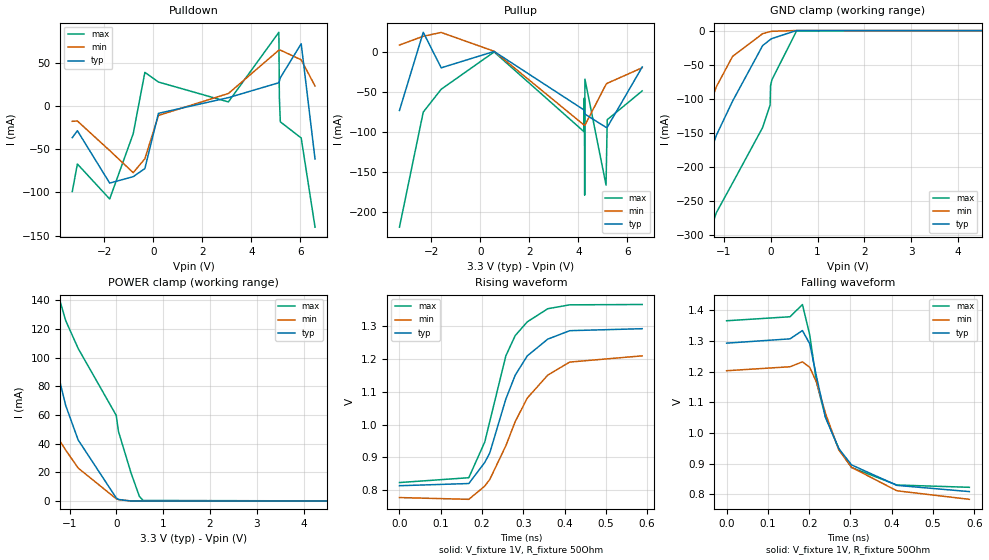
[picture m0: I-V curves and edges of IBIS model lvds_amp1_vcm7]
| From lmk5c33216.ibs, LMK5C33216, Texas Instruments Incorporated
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[Model]   lvds_amp1_vcm7
Model_type   Output
Polarity   Non-Inverting
Vmeas = 1.05
Vref = 1
Cref = 0pF
Rref = 50
|   typ   min   max
C_comp   0.65pF   0.575pF   0.725pF
[Voltage Range]   3.3   3.135   3.465
[Temperature Range]   50   135   -40
[Pullup Reference]   3.3   3.135   3.465
[Pulldown Reference]   0   0   0
[Power Clamp Reference]   3.3   3.135   3.465
[GND Clamp Reference]   0   0   0
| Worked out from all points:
|   slope of the pulldown table from 0 to 0.495 V, typ, clamps not added: 39 ohm
|   slope of the pullup table from 0 to 0.495 V, typ, clamps not added: 45.2 ohm
|   falling waveform, V_fixture 1V, R_fixture 50Ohm: 20-80 % time 80ps typ, 90.8ps min, 72ps max; typ from 1.29 V to 0.809 V
|   rising waveform, V_fixture 1V, R_fixture 50Ohm: 20-80 % time 84.3ps typ, 103ps min, 72.7ps max; typ from 0.813 V to 1.29 V
[Pulldown]
|   Voltage   I(typ)   I(min)   I(max)
-3.3V     -36.28mA   -17.29mA   -98.91mA
-3.092V   -28.2mA    -16.94mA   -66.89mA
-1.775V   -89.1mA    -51.28mA   -107.6mA
-815.1mV  -81.61mA   -77mA      -31.67mA
-339.9mV  -72.2mA    -60.81mA   39.58mA
214.5mV   -8.027mA   -10.45mA   28.36mA
3.066V    10.19mA    15.04mA    5.226mA
5.125V    27.53mA    65.4mA     86.12mA
5.145V    29.31mA    65.43mA    11.13mA
5.184V    33.29mA    65.5mA     -17.89mA
6.036V    72.89mA    54.18mA    -36.69mA
6.6V      -61.2mA    23.69mA    -140.3mA
[GND Clamp]
|   Voltage   I(typ)   I(min)   I(max)
-3.3V     -892.9mA   -765.6mA   -1.068A
-1.924V   -314.6mA   -288.5mA   -459.9mA
-1.815V   -287mA     -251.4mA   -425.6mA
-1.478V   -218.2mA   -143.5mA   -333.1mA
-1.162V   -154.3mA   -82.94mA   -268mA
-815.1mV  -104mA     -38.12mA   -224.4mA
-171.6mV  -22.09mA   -4.573mA   -142.5mA
-13.2mV   -13.46mA   -1.685mA   -109.6mA
-3.3mV    -13.01mA   -1.546mA   -81.34mA
26.4mV    -11.77mA   -1.169mA   -72.3mA
551.1mV   0A         -83.65nA   -742.8uA
6.6V      0A         0A         0A
[Pullup]
|   Voltage   I(typ)   I(min)   I(max)
-3.3V     -73.54mA   8.067mA    -219.2mA
-2.33V    23.94mA    19.04mA    -75.63mA
-1.597V   -20.36mA   23.77mA    -47.07mA
561mV     65.53uA    296.6uA    -559.4uA
4.224V    -72.89mA   -91.67mA   -99.99mA
4.234V    -74.22mA   -91.78mA   -58.17mA
4.244V    -75.55mA   -91.87mA   -59.21mA
4.254V    -76.87mA   -91.95mA   -179.3mA
4.264V    -78.2mA    -92.03mA   -34.54mA
5.125V    -94.66mA   -41.01mA   -166.7mA
5.174V    -94.58mA   -39.64mA   -85.12mA
6.6V      -19.36mA   -20.28mA   -49.19mA
[POWER Clamp]
|   Voltage   I(typ)   I(min)   I(max)
-3.3V     330.7mA    180mA      566.4mA
-2.736V   200mA      135.8mA    401.6mA
-1.647V   138.3mA    65.17mA    197.7mA
-1.459V   117.6mA    55.06mA    168.7mA
-1.082V   66.76mA    35.64mA    126mA
-815.1mV  42.67mA    23.06mA    106.5mA
-3.3mV    2.23mA     1.644mA    59.86mA
46.2mV    1.16mA     1.045mA    48.46mA
313.5mV   86.42uA    94.45uA    19.62mA
491.7mV   74.41uA    72.76uA    3.272mA
570.9mV   69.96uA    68.47uA    464.6uA
6.6V      0A         0A         0A
[Ramp]
R_load = 50
|   typ   min   max
dV/dt_r   0.288342/8.39842e-11   0.259797/1.02328e-10   0.326583/7.24332e-11
dV/dt_f   0.290201/7.94865e-11   0.251526/9.06222e-11   0.325865/7.1979e-11
[Falling Waveform]
V_fixture = 1V
V_fixture_min = 0.95V
V_fixture_max = 1.05V
R_fixture = 50Ohm
C_fixture = 0F
|   Time   V(typ)   V(min)   V(max)
0s        1.293V     1.203V     1.366V
153.7ps   1.307V     1.216V     1.379V
183.6ps   1.334V     1.232V     1.419V
201.3ps   1.291V     1.214V     1.32V
218ps     1.182V     1.165V     1.164V
239.4ps   1.051V     1.064V     1.052V
271.6ps   948.9mV    945mV      949.6mV
302.7ps   895.8mV    887.8mV    887.4mV
412.5ps   829.1mV    811.4mV    830.3mV
588ps     808.8mV    783.6mV    822.8mV
[Rising Waveform]
V_fixture = 1V
V_fixture_min = 0.95V
V_fixture_max = 1.05V
R_fixture = 50Ohm
C_fixture = 0F
|   Time   V(typ)   V(min)   V(max)
0s        812.9mV    776.7mV    822.6mV
168ps     819.6mV    771.3mV    837.4mV
206.7ps   884.2mV    811.9mV    946.9mV
218.7ps   913mV      831.9mV    1.009V
257.7ps   1.078V     935.1mV    1.21V
280.4ps   1.151V     1.009V     1.272V
309.7ps   1.21V      1.081V     1.314V
359.1ps   1.261V     1.151V     1.354V
412.5ps   1.287V     1.191V     1.366V
588ps     1.293V     1.21V      1.367V
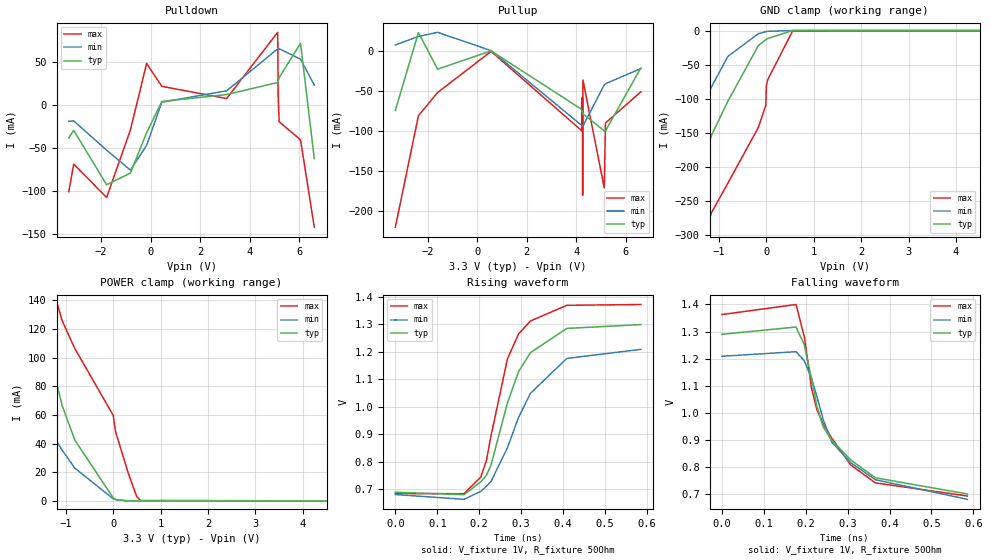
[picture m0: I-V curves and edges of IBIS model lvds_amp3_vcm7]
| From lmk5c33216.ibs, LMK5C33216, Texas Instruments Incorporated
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[Model]   lvds_amp3_vcm7
Model_type   Output
Polarity   Non-Inverting
Vmeas = 1
Vref = 1
Cref = 0pF
Rref = 50
|   typ   min   max
C_comp   0.65pF   0.575pF   0.725pF
[Voltage Range]   3.3   3.135   3.465
[Temperature Range]   50   135   -40
[Pullup Reference]   3.3   3.135   3.465
[Pulldown Reference]   -0   0   0
[Power Clamp Reference]   3.3   3.135   3.465
[GND Clamp Reference]   0   0   0
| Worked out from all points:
|   slope of the pulldown table from 0 to 0.495 V, typ, clamps not added: 36.3 ohm
|   slope of the pullup table from 0 to 0.495 V, typ, clamps not added: 44.7 ohm
|   falling waveform, V_fixture 1V, R_fixture 50Ohm: 20-80 % time 105ps typ, 114ps min, 96.3ps max; typ from 1.29 V to 0.701 V
|   rising waveform, V_fixture 1V, R_fixture 50Ohm: 20-80 % time 79.3ps typ, 97.9ps min, 63.7ps max; typ from 0.69 V to 1.3 V
[Pulldown]
|   Voltage   I(typ)   I(min)   I(max)
-3.3V     -38.24mA   -18.97mA   -101mA
-3.102V   -29.52mA   -18.51mA   -68.88mA
-1.775V   -92.97mA   -52.57mA   -107.8mA
-815.1mV  -79.32mA   -75.88mA   -29.05mA
-161.7mV  -32.41mA   -46.99mA   48.34mA
452.1mV   4.115mA    3.224mA    21.7mA
3.066V    12.13mA    16.52mA    7.51mA
5.125V    26.21mA    65.37mA    84.62mA
5.145V    27.96mA    65.4mA     9.43mA
5.184V    31.9mA     65.46mA    -19.52mA
6.046V    71.81mA    53.32mA    -40.66mA
6.6V      -62.49mA   23.18mA    -142.3mA
[GND Clamp]
|   Voltage   I(typ)   I(min)   I(max)
-3.3V     -892.9mA   -765.6mA   -1.068A
-1.924V   -314.6mA   -288.5mA   -459.9mA
-1.815V   -287mA     -251.4mA   -425.6mA
-1.478V   -218.2mA   -143.5mA   -333.1mA
-1.162V   -154.3mA   -82.94mA   -268mA
-815.1mV  -104mA     -38.12mA   -224.4mA
-171.6mV  -22.09mA   -4.573mA   -142.5mA
-13.2mV   -13.46mA   -1.685mA   -109.6mA
-3.3mV    -13.01mA   -1.546mA   -81.32mA
26.4mV    -11.77mA   -1.169mA   -72.35mA
551.1mV   0A         -83.65nA   -742.8uA
6.6V      0A         0A         0A
[Pullup]
|   Voltage   I(typ)   I(min)   I(max)
-3.3V     -74.36mA   7.532mA    -220.4mA
-2.369V   23.05mA    18.16mA    -81mA
-1.597V   -22.71mA   23.36mA    -51.97mA
561mV     135.2uA    475.5uA    -547.1uA
4.224V    -73.22mA   -93.37mA   -99.9mA
4.234V    -74.59mA   -93.52mA   -58.1mA
4.244V    -75.96mA   -93.67mA   -59.14mA
4.254V    -77.33mA   -93.8mA    -180.7mA
4.264V    -78.7mA    -93.93mA   -36.28mA
5.125V    -99.86mA   -42.33mA   -171.2mA
5.174V    -99.93mA   -40.98mA   -90.01mA
6.6V      -21.2mA    -21.98mA   -51.16mA
[POWER Clamp]
|   Voltage   I(typ)   I(min)   I(max)
-3.3V     330.7mA    180mA      566.4mA
-2.736V   200mA      135.8mA    401.6mA
-1.647V   138.3mA    65.17mA    197.7mA
-1.459V   117.6mA    55.06mA    168.7mA
-1.082V   66.76mA    35.64mA    126mA
-815.1mV  42.67mA    23.06mA    106.5mA
-3.3mV    2.23mA     1.644mA    59.85mA
46.2mV    1.16mA     1.045mA    48.48mA
313.5mV   86.42uA    94.45uA    19.62mA
491.7mV   74.41uA    72.76uA    3.272mA
570.9mV   69.96uA    68.47uA    464.6uA
6.6V      0A         0A         0A
[Ramp]
R_load = 50
|   typ   min   max
dV/dt_r   0.365402/7.91052e-11   0.316822/9.78563e-11   0.412328/6.33514e-11
dV/dt_f   0.353145/1.04143e-10   0.316822/1.12557e-10   0.401376/9.55052e-11
[Falling Waveform]
V_fixture = 1V
V_fixture_min = 0.95V
V_fixture_max = 1.05V
R_fixture = 50Ohm
C_fixture = 0F
|   Time   V(typ)   V(min)   V(max)
0s        1.29V      1.209V     1.363V
176.9ps   1.317V     1.226V     1.4V
196.7ps   1.251V     1.192V     1.281V
213.9ps   1.126V     1.128V     1.091V
226.7ps   1.025V     1.061V     1.012V
241.5ps   949.1mV    976.7mV    961.3mV
261.4ps   900.6mV    894mV      909.1mV
307.6ps   826mV      816.2mV    807.7mV
366.6ps   760.7mV    753.5mV    742mV
585.8ps   701.1mV    681.4mV    693.7mV
[Rising Waveform]
V_fixture = 1V
V_fixture_min = 0.95V
V_fixture_max = 1.05V
R_fixture = 50Ohm
C_fixture = 0F
|   Time   V(typ)   V(min)   V(max)
0s        689.7mV    681.4mV    684.9mV
163.7ps   680.9mV    664mV      684.6mV
203.8ps   727.5mV    692.7mV    744.5mV
217.3ps   751.4mV    711.3mV    805.1mV
228ps     787.4mV    727.8mV    892.9mV
267.4ps   1.014V     851.3mV    1.174V
294ps     1.128V     961.8mV    1.265V
322.3ps   1.197V     1.049V     1.312V
409.1ps   1.285V     1.176V     1.369V
585.8ps   1.299V     1.209V     1.372V
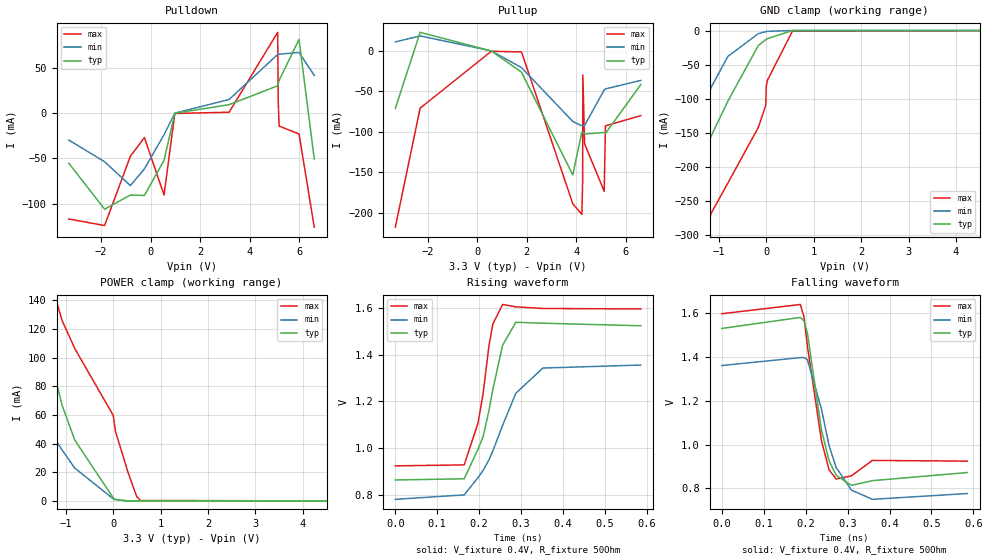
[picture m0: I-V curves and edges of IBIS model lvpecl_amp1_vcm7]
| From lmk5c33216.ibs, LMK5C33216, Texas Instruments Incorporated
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[Model]   lvpecl_amp1_vcm7
Model_type   Output
Polarity   Non-Inverting
Vmeas = 1.2
Vref = 0.4
Cref = 0pF
Rref = 50
|   typ   min   max
C_comp   0.65pF   0.575pF   0.725pF
[Voltage Range]   3.3   3.135   3.465
[Temperature Range]   50   135   -40
[Pullup Reference]   3.3   3.135   3.465
[Pulldown Reference]   0   0   0
[Power Clamp Reference]   3.3   3.135   3.465
[GND Clamp Reference]   0   0   0
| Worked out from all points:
|   slope of the pulldown table from 0 to 0.495 V, typ, clamps not added: 17.6 ohm
|   slope of the pullup table from 0 to 0.495 V, typ, clamps not added: 52.3 ohm
|   falling waveform, V_fixture 0.4V, R_fixture 50Ohm: 20-80 % time 31.6ps typ, 43.8ps min, 30.3ps max; typ from 1.53 V to 0.873 V
|   rising waveform, V_fixture 0.4V, R_fixture 50Ohm: 20-80 % time 51.5ps typ, 83.6ps min, 38.7ps max; typ from 0.864 V to 1.52 V
[Pulldown]
|   Voltage   I(typ)   I(min)   I(max)
-3.3V     -55.54mA   -29.94mA   -117.1mA
-1.855V   -106.3mA   -53.89mA   -124.3mA
-815.1mV  -90.62mA   -80.2mA    -47.75mA
-250.8mV  -91.11mA   -61.75mA   -27.15mA
541.2mV   -52.28mA   -24.04mA   -90.66mA
976.8mV   -331.6uA   -179.7uA   -555.2uA
3.165V    9.147mA    14.84mA    773.9uA
5.125V    29.99mA    64.61mA    89.03mA
5.145V    31.87mA    64.67mA    14.18mA
5.184V    36.04mA    64.81mA    -14.5mA
5.986V    81.17mA    66.88mA    -23.15mA
6.6V      -50.8mA    41.43mA    -126.1mA
[GND Clamp]
|   Voltage   I(typ)   I(min)   I(max)
-3.3V     -892.9mA   -765.6mA   -1.068A
-1.924V   -314.6mA   -288.5mA   -459.9mA
-1.815V   -287mA     -251.4mA   -425.6mA
-1.478V   -218.2mA   -143.5mA   -333.1mA
-1.162V   -154.3mA   -82.94mA   -268mA
-815.1mV  -104mA     -38.12mA   -224.4mA
-171.6mV  -22.09mA   -4.573mA   -142.5mA
-13.2mV   -13.46mA   -1.685mA   -109.6mA
-3.3mV    -13.01mA   -1.546mA   -81.32mA
26.4mV    -11.77mA   -1.169mA   -72.35mA
551.1mV   0A         -83.65nA   -742.3uA
6.6V      0A         0A         0A
[Pullup]
|   Voltage   I(typ)   I(min)   I(max)
-3.3V     -71.11mA   11.11mA    -217.9mA
-2.3V     23.01mA    18.59mA    -70.78mA
570.9mV   -34.73uA   26.91uA    -439.3uA
1.789V    -26.25mA   -20.59mA   -1.263mA
3.858V    -153.3mA   -87.25mA   -189mA
4.224V    -100.2mA   -92.59mA   -202.1mA
4.254V    -100.4mA   -92.51mA   -162.3mA
4.264V    -100.6mA   -92.48mA   -29.78mA
4.333V    -102.7mA   -92.17mA   -114.8mA
5.125V    -100.8mA   -48.19mA   -173.6mA
5.174V    -102.1mA   -46.97mA   -92.64mA
6.6V      -41.61mA   -36.46mA   -79.99mA
[POWER Clamp]
|   Voltage   I(typ)   I(min)   I(max)
-3.3V     330.7mA    180mA      566.4mA
-2.736V   200mA      135.8mA    401.6mA
-1.647V   138.3mA    65.17mA    197.7mA
-1.459V   117.6mA    55.06mA    168.7mA
-1.082V   66.76mA    35.64mA    126mA
-815.1mV  42.67mA    23.06mA    106.5mA
-3.3mV    2.23mA     1.644mA    59.85mA
46.2mV    1.16mA     1.045mA    48.48mA
313.5mV   86.42uA    94.45uA    19.62mA
491.7mV   74.41uA    72.76uA    3.272mA
570.9mV   69.96uA    68.47uA    464.4uA
6.6V      0A         0A         0A
[Ramp]
R_load = 50
|   typ   min   max
dV/dt_r   0.395728/5.12019e-11   0.345023/8.32962e-11   0.402849/3.86156e-11
dV/dt_f   0.393848/3.15675e-11   0.349741/4.38037e-11   0.402849/3.0072e-11
[Falling Waveform]
V_fixture = 0.4V
V_fixture_min = 0.35V
V_fixture_max = 0.45V
R_fixture = 50Ohm
C_fixture = 0F
|   Time   V(typ)   V(min)   V(max)
0s        1.529V     1.36V      1.596V
187.2ps   1.579V     1.396V     1.638V
195.9ps   1.563V     1.396V     1.582V
204.1ps   1.507V     1.387V     1.448V
237.7ps   1.066V     1.161V     1.017V
255.8ps   926.2mV    995.3mV    884.9mV
272.6ps   860.1mV    895.7mV    843.1mV
309.1ps   814.2mV    792.7mV    857.3mV
359.1ps   835.5mV    750.5mV    927.8mV
585.6ps   872.6mV    776.9mV    924.5mV
[Rising Waveform]
V_fixture = 0.4V
V_fixture_min = 0.35V
V_fixture_max = 0.45V
R_fixture = 50Ohm
C_fixture = 0F
|   Time   V(typ)   V(min)   V(max)
0s        864.1mV    781.2mV    924.5mV
164.3ps   869.1mV    800.2mV    928.6mV
197.4ps   996.6mV    874.3mV    1.108V
209.7ps   1.051V     905.7mV    1.237V
223ps     1.158V     948.8mV    1.434V
232.7ps   1.252V     988.7mV    1.532V
255.8ps   1.44V      1.097V     1.615V
287.5ps   1.539V     1.235V     1.605V
351.8ps   1.535V     1.343V     1.598V
585.6ps   1.524V     1.356V     1.596V
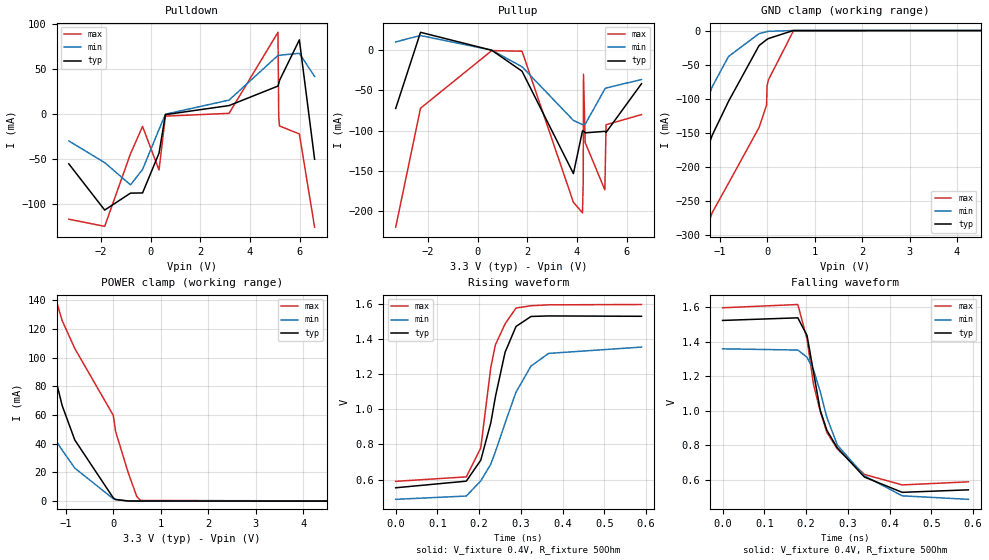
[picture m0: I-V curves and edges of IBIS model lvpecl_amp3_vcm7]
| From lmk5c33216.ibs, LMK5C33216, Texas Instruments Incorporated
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[Model]   lvpecl_amp3_vcm7
Model_type   Output
Polarity   Non-Inverting
Vmeas = 1.05
Vref = 0.4
Cref = 0pF
Rref = 50
|   typ   min   max
C_comp   0.65pF   0.575pF   0.725pF
[Voltage Range]   3.3   3.135   3.465
[Temperature Range]   50   135   -40
[Pullup Reference]   3.3   3.135   3.465
[Pulldown Reference]   0   0   -0
[Power Clamp Reference]   3.3   3.135   3.465
[GND Clamp Reference]   0   0   0
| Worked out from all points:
|   slope of the pulldown table from 0 to 0.495 V, typ, clamps not added: 8.61 ohm
|   slope of the pullup table from 0 to 0.495 V, typ, clamps not added: 51.2 ohm
|   falling waveform, V_fixture 0.4V, R_fixture 50Ohm: 20-80 % time 78.5ps typ, 97ps min, 67ps max; typ from 1.52 V to 0.544 V
|   rising waveform, V_fixture 0.4V, R_fixture 50Ohm: 20-80 % time 52.4ps typ, 82.5ps min, 38.5ps max; typ from 0.553 V to 1.53 V
[Pulldown]
|   Voltage   I(typ)   I(min)   I(max)
-3.3V     -55.26mA   -29.89mA   -116.5mA
-1.855V   -106.4mA   -53.89mA   -124.4mA
-815.1mV  -87.64mA   -78.47mA   -44.04mA
-330mV    -87.45mA   -61.5mA    -13.86mA
333.3mV   -43.46mA   -17.19mA   -62.07mA
590.7mV   -792.1uA   -335.3uA   -2.433mA
3.155V    9.24mA     15.3mA     640.1uA
5.125V    30.83mA    64.73mA    90.29mA
5.155V    33.7mA     64.83mA    -2.221mA
5.184V    36.87mA    64.93mA    -13.27mA
5.986V    81.94mA    67.08mA    -22.17mA
6.6V      -50.08mA   41.43mA    -125.3mA
[GND Clamp]
|   Voltage   I(typ)   I(min)   I(max)
-3.3V     -892.9mA   -765.6mA   -1.068A
-1.924V   -314.6mA   -288.5mA   -459.9mA
-1.815V   -287mA     -251.4mA   -425.6mA
-1.478V   -218.2mA   -143.5mA   -333.1mA
-1.162V   -154.3mA   -82.94mA   -268mA
-815.1mV  -104mA     -38.12mA   -224.4mA
-171.6mV  -22.09mA   -4.573mA   -142.5mA
-13.2mV   -13.46mA   -1.685mA   -109.6mA
-3.3mV    -13.01mA   -1.546mA   -81.32mA
26.4mV    -11.77mA   -1.169mA   -72.35mA
551.1mV   0A         -83.65nA   -740.5uA
6.6V      0A         0A         0A
[Pullup]
|   Voltage   I(typ)   I(min)   I(max)
-3.3V     -72.34mA   10.4mA     -219.9mA
-2.3V     22.26mA    18.26mA    -72.06mA
570.9mV   -25.45uA   42.59uA    -437.4uA
1.789V    -26.09mA   -20.56mA   -1.222mA
3.858V    -153.3mA   -87.2mA    -189mA
4.224V    -100.2mA   -92.4mA    -202.1mA
4.254V    -100.4mA   -92.29mA   -162.3mA
4.264V    -100.6mA   -92.25mA   -29.8mA
4.333V    -102.7mA   -91.88mA   -114.8mA
5.125V    -100.8mA   -48.13mA   -173.6mA
5.174V    -102.1mA   -46.91mA   -92.62mA
6.6V      -41.65mA   -36.46mA   -80.03mA
[POWER Clamp]
|   Voltage   I(typ)   I(min)   I(max)
-3.3V     330.7mA    180mA      566.4mA
-2.736V   200mA      135.8mA    401.6mA
-1.647V   138.3mA    65.17mA    197.7mA
-1.459V   117.6mA    55.06mA    168.7mA
-1.082V   66.76mA    35.64mA    126mA
-815.1mV  42.67mA    23.06mA    106.5mA
-3.3mV    2.23mA     1.644mA    59.85mA
46.2mV    1.16mA     1.045mA    48.48mA
313.5mV   86.41uA    94.45uA    19.62mA
491.7mV   74.41uA    72.76uA    3.272mA
570.9mV   69.96uA    68.47uA    463.8uA
6.6V      0A         0A         0A
[Ramp]
R_load = 50
|   typ   min   max
dV/dt_r   0.584996/5.22393e-11   0.519051/8.21709e-11   0.603231/3.83802e-11
dV/dt_f   0.586924/7.84924e-11   0.521551/9.61248e-11   0.603231/6.70456e-11
[Falling Waveform]
V_fixture = 0.4V
V_fixture_min = 0.35V
V_fixture_max = 0.45V
R_fixture = 50Ohm
C_fixture = 0F
|   Time   V(typ)   V(min)   V(max)
0s        1.522V     1.358V     1.595V
180.2ps   1.537V     1.351V     1.614V
202.2ps   1.435V     1.309V     1.414V
217.7ps   1.224V     1.237V     1.154V
233.6ps   1.006V     1.113V     999.3mV
249.7ps   887.5mV    962.2mV    875.8mV
274.9ps   785.2mV    801.7mV    779.1mV
339.8ps   617.2mV    624.6mV    632.5mV
430.2ps   529.2mV    509mV      572mV
588.6ps   543.6mV    488.8mV    589.9mV
[Rising Waveform]
V_fixture = 0.4V
V_fixture_min = 0.35V
V_fixture_max = 0.45V
R_fixture = 50Ohm
C_fixture = 0F
|   Time   V(typ)   V(min)   V(max)
0s        553.3mV    487.6mV    589.9mV
169ps     590.9mV    506.3mV    615.2mV
203.7ps   710.1mV    592.4mV    779.7mV
227.8ps   922.8mV    687.9mV    1.238V
238.8ps   1.071V     758.5mV    1.366V
262ps     1.324V     921.3mV    1.485V
288.1ps   1.47V      1.097V     1.575V
324.1ps   1.527V     1.245V     1.588V
366.2ps   1.53V      1.317V     1.593V
588.6ps   1.528V     1.353V     1.595V
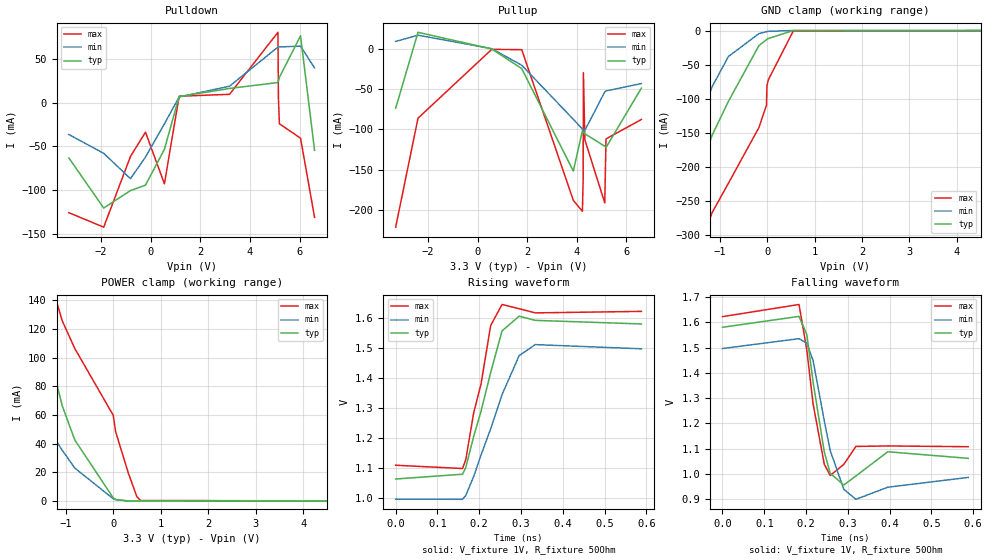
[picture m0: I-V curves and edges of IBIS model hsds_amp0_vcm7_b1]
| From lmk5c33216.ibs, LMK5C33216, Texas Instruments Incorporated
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[Model]   hsds_amp0_vcm7_b1
Model_type   Output
Polarity   Non-Inverting
Vmeas = 1.3
Vref = 1
Cref = 0pF
Rref = 50
|   typ   min   max
C_comp   0.65pF   0.575pF   0.725pF
[Voltage Range]   3.3   3.135   3.465
[Temperature Range]   50   135   -40
[Pullup Reference]   3.3   3.135   3.465
[Pulldown Reference]   -0   0   0
[Power Clamp Reference]   3.3   3.135   3.465
[GND Clamp Reference]   0   0   0
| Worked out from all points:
|   slope of the pulldown table from 0 to 0.495 V, typ, clamps not added: 16.9 ohm
|   slope of the pullup table from 0 to 0.495 V, typ, clamps not added: 49.5 ohm
|   falling waveform, V_fixture 1V, R_fixture 50Ohm: 20-80 % time 26ps typ, 35.1ps min, 22.9ps max; typ from 1.58 V to 1.06 V
|   rising waveform, V_fixture 1V, R_fixture 50Ohm: 20-80 % time 56.5ps typ, 74.9ps min, 41.7ps max; typ from 1.06 V to 1.58 V
[Pulldown]
|   Voltage   I(typ)   I(min)   I(max)
-3.3V     -63.04mA   -36.4mA    -125.5mA
-1.894V   -120.2mA   -57.89mA   -142mA
-815.1mV  -100.3mA   -86.75mA   -61.41mA
-211.2mV  -94.11mA   -62.11mA   -33.75mA
551.1mV   -53.3mA    -24.3mA    -92.6mA
1.145V    6.838mA    6.321mA    7.199mA
3.175V    16.06mA    18.64mA    9.395mA
5.125V    22.83mA    63.22mA    80.03mA
5.145V    24.64mA    63.28mA    4.947mA
5.184V    28.69mA    63.39mA    -24.16mA
6.036V    76.06mA    64.28mA    -40.61mA
6.6V      -54.38mA   39.44mA    -130.8mA
[GND Clamp]
|   Voltage   I(typ)   I(min)   I(max)
-3.3V     -892.9mA   -765.6mA   -1.068A
-1.924V   -314.6mA   -288.5mA   -459.9mA
-1.815V   -287mA     -251.4mA   -425.6mA
-1.478V   -218.2mA   -143.5mA   -333.1mA
-1.162V   -154.3mA   -82.94mA   -268mA
-815.1mV  -104mA     -38.12mA   -224.4mA
-171.6mV  -22.09mA   -4.573mA   -142.5mA
-13.2mV   -13.46mA   -1.685mA   -109.6mA
-3.3mV    -13.01mA   -1.546mA   -81.32mA
26.4mV    -11.77mA   -1.169mA   -72.35mA
551.1mV   0A         -83.65nA   -742.3uA
6.6V      0A         0A         0A
[Pullup]
|   Voltage   I(typ)   I(min)   I(max)
-3.3V     -73.65mA   9.44mA     -221.4mA
-2.399V   20.74mA    17.16mA    -85.97mA
570.9mV   58.36uA    437.1uA    -433.7uA
1.779V    -24.35mA   -20.15mA   -811.2uA
3.858V    -151.7mA   -87.38mA   -188.1mA
4.224V    -101.4mA   -99.44mA   -201.6mA
4.254V    -102.2mA   -99.99mA   -161.8mA
4.264V    -102.5mA   -100.2mA   -29.37mA
4.323V    -105.4mA   -101.1mA   -112.9mA
5.125V    -120.8mA   -53.31mA   -191.3mA
5.174V    -122.5mA   -52.15mA   -111.7mA
6.6V      -48.6mA    -42.92mA   -87.59mA
[POWER Clamp]
|   Voltage   I(typ)   I(min)   I(max)
-3.3V     330.7mA    180mA      566.4mA
-2.736V   200mA      135.8mA    401.6mA
-1.647V   138.3mA    65.17mA    197.7mA
-1.459V   117.6mA    55.06mA    168.7mA
-1.082V   66.76mA    35.64mA    126mA
-815.1mV  42.67mA    23.06mA    106.5mA
-3.3mV    2.23mA     1.644mA    59.85mA
46.2mV    1.16mA     1.045mA    48.48mA
313.5mV   86.42uA    94.45uA    19.62mA
491.7mV   74.41uA    72.76uA    3.272mA
570.9mV   69.96uA    68.47uA    464.4uA
6.6V      0A         0A         0A
[Ramp]
R_load = 50
|   typ   min   max
dV/dt_r   0.310756/5.65935e-11   0.301042/7.46586e-11   0.308701/4.17032e-11
dV/dt_f   0.310756/2.57787e-11   0.305774/3.47797e-11   0.308701/2.27165e-11
[Falling Waveform]
V_fixture = 1V
V_fixture_min = 0.95V
V_fixture_max = 1.05V
R_fixture = 50Ohm
C_fixture = 0F
|   Time   V(typ)   V(min)   V(max)
0s        1.58V      1.496V     1.622V
183.2ps   1.623V     1.535V     1.67V
201.9ps   1.551V     1.517V     1.489V
216.9ps   1.363V     1.448V     1.277V
243.6ps   1.088V     1.211V     1.039V
257.8ps   1.003V     1.093V     994.1mV
290.3ps   956.6mV    939.8mV    1.038V
319.3ps   992.4mV    900mV      1.109V
395.7ps   1.088V     947.9mV    1.111V
588.2ps   1.062V     986.6mV    1.108V
[Rising Waveform]
V_fixture = 1V
V_fixture_min = 0.95V
V_fixture_max = 1.05V
R_fixture = 50Ohm
C_fixture = 0F
|   Time   V(typ)   V(min)   V(max)
0s        1.062V     994.9mV    1.108V
160.1ps   1.078V     994.1mV    1.097V
167.9ps   1.101V     1.007V     1.127V
186.9ps   1.205V     1.071V     1.284V
204.3ps   1.288V     1.142V     1.379V
227.5ps   1.418V     1.23V      1.575V
254.7ps   1.557V     1.344V     1.645V
295.6ps   1.606V     1.474V     1.631V
334.1ps   1.592V     1.511V     1.617V
588.2ps   1.58V      1.497V     1.622V
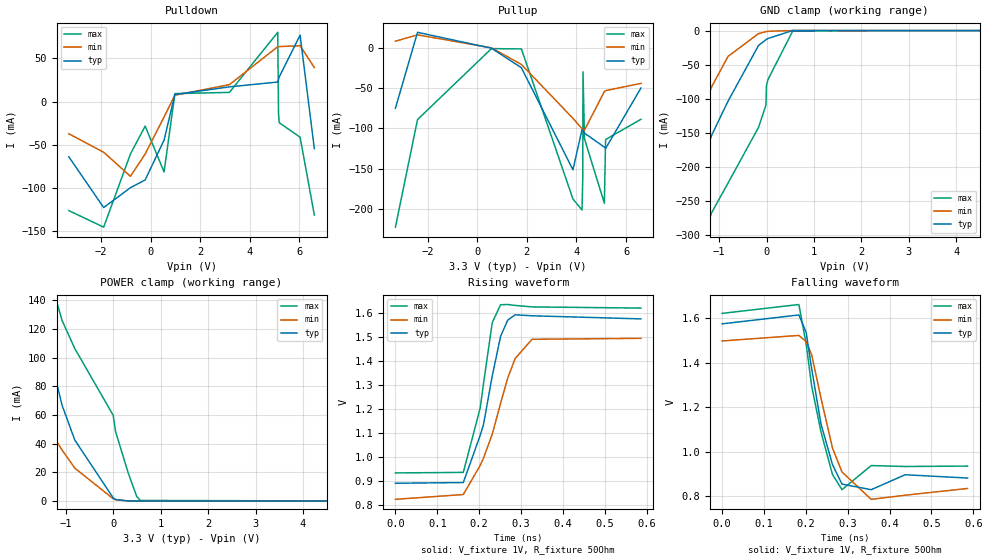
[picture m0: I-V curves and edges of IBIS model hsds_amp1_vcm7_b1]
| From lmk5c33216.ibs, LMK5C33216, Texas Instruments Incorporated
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[Model]   hsds_amp1_vcm7_b1
Model_type   Output
Polarity   Non-Inverting
Vmeas = 1.25
Vref = 1
Cref = 0pF
Rref = 50
|   typ   min   max
C_comp   0.65pF   0.575pF   0.725pF
[Voltage Range]   3.3   3.135   3.465
[Temperature Range]   50   135   -40
[Pullup Reference]   3.3   3.135   3.465
[Pulldown Reference]   0   0   0
[Power Clamp Reference]   3.3   3.135   3.465
[GND Clamp Reference]   0   0   0
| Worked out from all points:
|   slope of the pulldown table from 0 to 0.495 V, typ, clamps not added: 15 ohm
|   slope of the pullup table from 0 to 0.495 V, typ, clamps not added: 49.1 ohm
|   falling waveform, V_fixture 1V, R_fixture 50Ohm: 20-80 % time 40.9ps typ, 49.4ps min, 37.4ps max; typ from 1.57 V to 0.881 V
|   rising waveform, V_fixture 1V, R_fixture 50Ohm: 20-80 % time 52.4ps typ, 73.8ps min, 41.9ps max; typ from 0.892 V to 1.58 V
[Pulldown]
|   Voltage   I(typ)   I(min)   I(max)
-3.3V     -63.77mA   -37.21mA   -125.9mA
-1.894V   -122.4mA   -58.55mA   -145mA
-815.1mV  -99.47mA   -86.32mA   -60.59mA
-221.1mV  -90.5mA    -60.57mA   -28.37mA
541.2mV   -44.59mA   -17.87mA   -81.33mA
976.8mV   8.047mA    7.282mA    9.101mA
3.175V    16.92mA    19.43mA    10.51mA
5.125V    22.48mA    63.2mA     79.83mA
5.155V    25.22mA    63.28mA    -13.02mA
5.184V    28.3mA     63.36mA    -24.45mA
6.026V    76.6mA     64.4mA     -41.21mA
6.6V      -54.42mA   39.18mA    -130.9mA
[GND Clamp]
|   Voltage   I(typ)   I(min)   I(max)
-3.3V     -892.9mA   -765.6mA   -1.068A
-1.924V   -314.6mA   -288.5mA   -459.9mA
-1.815V   -287mA     -251.4mA   -425.6mA
-1.478V   -218.2mA   -143.5mA   -333.1mA
-1.162V   -154.3mA   -82.94mA   -268mA
-815.1mV  -104mA     -38.12mA   -224.4mA
-171.6mV  -22.09mA   -4.573mA   -142.5mA
-13.2mV   -13.46mA   -1.685mA   -109.6mA
-3.3mV    -13.01mA   -1.546mA   -81.32mA
26.4mV    -11.77mA   -1.169mA   -72.35mA
551.1mV   0A         -83.65nA   -744.1uA
6.6V      0A         0A         0A
[Pullup]
|   Voltage   I(typ)   I(min)   I(max)
-3.3V     -74.76mA   8.805mA    -223mA
-2.409V   19.9mA     16.76mA    -88.9mA
570.9mV   102.6uA    560.8uA    -429.5uA
1.779V    -24.24mA   -20.13mA   -793.9uA
3.858V    -151.5mA   -87.37mA   -187.9mA
4.224V    -101.5mA   -100.2mA   -201.6mA
4.254V    -102.4mA   -100.8mA   -161.8mA
4.264V    -102.7mA   -101mA     -29.38mA
4.323V    -105.8mA   -102.1mA   -112.8mA
5.125V    -123.2mA   -53.95mA   -193.2mA
5.174V    -125mA     -52.8mA    -113.8mA
6.6V      -49.52mA   -43.76mA   -88.59mA
[POWER Clamp]
|   Voltage   I(typ)   I(min)   I(max)
-3.3V     330.7mA    180mA      566.4mA
-2.736V   200mA      135.8mA    401.6mA
-1.647V   138.3mA    65.17mA    197.7mA
-1.459V   117.6mA    55.06mA    168.7mA
-1.082V   66.76mA    35.64mA    126mA
-815.1mV  42.67mA    23.06mA    106.5mA
-3.3mV    2.23mA     1.644mA    59.85mA
46.2mV    1.16mA     1.045mA    48.48mA
313.5mV   86.42uA    94.45uA    19.62mA
491.7mV   74.41uA    72.76uA    3.272mA
570.9mV   69.96uA    68.47uA    464.4uA
6.6V      0A         0A         0A
[Ramp]
R_load = 50
|   typ   min   max
dV/dt_r   0.410986/5.23673e-11   0.40222/7.36888e-11   0.412108/4.19379e-11
dV/dt_f   0.416116/4.08637e-11   0.397981/4.93893e-11   0.412108/3.74547e-11
[Falling Waveform]
V_fixture = 1V
V_fixture_min = 0.95V
V_fixture_max = 1.05V
R_fixture = 50Ohm
C_fixture = 0F
|   Time   V(typ)   V(min)   V(max)
0s        1.575V     1.498V     1.622V
183.5ps   1.615V     1.523V     1.662V
200.9ps   1.536V     1.495V     1.484V
214.1ps   1.372V     1.435V     1.294V
236.4ps   1.124V     1.24V      1.088V
263.8ps   941.5mV    1.016V     897.1mV
286.4ps   854.1mV    908.9mV    829.1mV
356.2ps   828.9mV    785.6mV    937.5mV
437.3ps   896.2mV    804.1mV    933.3mV
586.3ps   881.3mV    834.5mV    935.2mV
[Rising Waveform]
V_fixture = 1V
V_fixture_min = 0.95V
V_fixture_max = 1.05V
R_fixture = 50Ohm
C_fixture = 0F
|   Time   V(typ)   V(min)   V(max)
0s        892.2mV    825.2mV    935.2mV
162.1ps   895.1mV    845.2mV    937.5mV
202.3ps   1.091V     966.2mV    1.205V
210.2ps   1.136V     996.2mV    1.305V
231.3ps   1.34V      1.097V     1.562V
251.1ps   1.504V     1.225V     1.636V
268.2ps   1.572V     1.331V     1.637V
286ps     1.594V     1.412V     1.633V
326.2ps   1.59V      1.492V     1.627V
586.3ps   1.577V     1.496V     1.622V
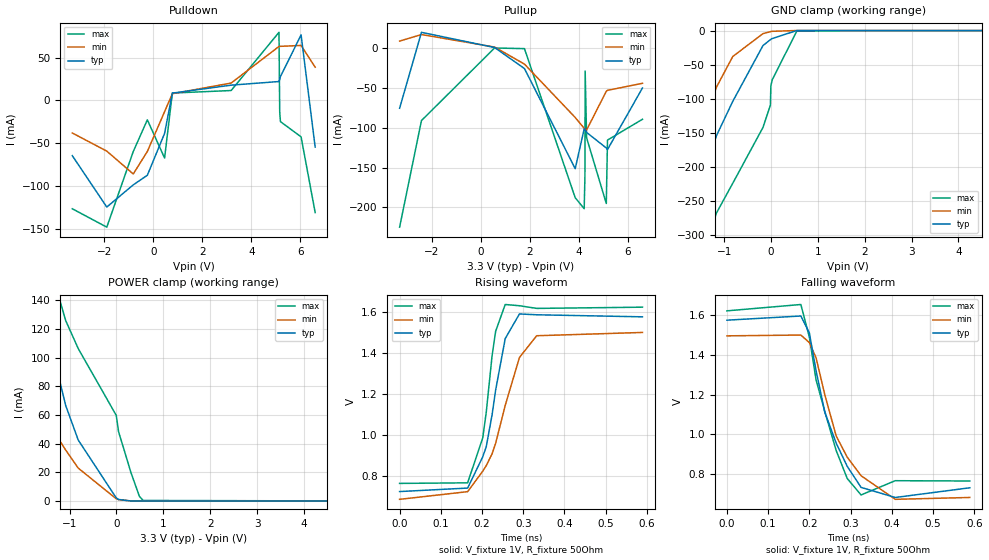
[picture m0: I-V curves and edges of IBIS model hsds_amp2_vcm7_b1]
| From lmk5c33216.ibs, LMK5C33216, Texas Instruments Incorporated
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[Model]   hsds_amp2_vcm7_b1
Model_type   Output
Polarity   Non-Inverting
Vmeas = 1.15
Vref = 1
Cref = 0pF
Rref = 50
|   typ   min   max
C_comp   0.65pF   0.575pF   0.725pF
[Voltage Range]   3.3   3.135   3.465
[Temperature Range]   50   135   -40
[Pullup Reference]   3.3   3.135   3.465
[Pulldown Reference]   -0   0   -0
[Power Clamp Reference]   3.3   3.135   3.465
[GND Clamp Reference]   0   0   0
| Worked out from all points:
|   slope of the pulldown table from 0 to 0.495 V, typ, clamps not added: 12.3 ohm
|   slope of the pullup table from 0 to 0.495 V, typ, clamps not added: 48.7 ohm
|   falling waveform, V_fixture 1V, R_fixture 50Ohm: 20-80 % time 67.1ps typ, 82.7ps min, 60.1ps max; typ from 1.57 V to 0.73 V
|   rising waveform, V_fixture 1V, R_fixture 50Ohm: 20-80 % time 46.9ps typ, 73.1ps min, 35.2ps max; typ from 0.725 V to 1.57 V
[Pulldown]
|   Voltage   I(typ)   I(min)   I(max)
-3.3V     -64.55mA   -38.02mA   -126.6mA
-1.894V   -124.6mA   -59.22mA   -148.1mA
-815.1mV  -98.66mA   -85.91mA   -59.7mA
-240.9mV  -87.41mA   -59.63mA   -22.63mA
462mV     -38.51mA   -13.1mA    -67.31mA
778.8mV   8.578mA    7.868mA    8.664mA
3.175V    17.9mA     20.36mA    11.62mA
5.125V    22.14mA    63.12mA    79.66mA
5.155V    24.86mA    63.2mA     -13.32mA
5.184V    27.91mA    63.29mA    -24.72mA
6.026V    76.65mA    64.31mA    -42.55mA
6.6V      -54.46mA   38.93mA    -131mA
[GND Clamp]
|   Voltage   I(typ)   I(min)   I(max)
-3.3V     -892.9mA   -765.6mA   -1.068A
-1.924V   -314.6mA   -288.5mA   -459.9mA
-1.815V   -287mA     -251.4mA   -425.6mA
-1.478V   -218.2mA   -143.5mA   -333.1mA
-1.162V   -154.3mA   -82.94mA   -268mA
-815.1mV  -104mA     -38.12mA   -224.4mA
-171.6mV  -22.09mA   -4.573mA   -142.5mA
-13.2mV   -13.46mA   -1.685mA   -109.6mA
-3.3mV    -13.01mA   -1.546mA   -81.32mA
26.4mV    -11.77mA   -1.169mA   -72.35mA
551.1mV   0A         -83.65nA   -742uA
6.6V      0A         0A         0A
[Pullup]
|   Voltage   I(typ)   I(min)   I(max)
-3.3V     -75.83mA   8.182mA    -224.6mA
-2.409V   19.18mA    16.4mA     -91.24mA
570.9mV   174.1uA    718.6uA    -421.2uA
1.789V    -26.15mA   -20.57mA   -1.24mA
3.858V    -151.4mA   -87.37mA   -187.8mA
4.224V    -101.6mA   -100.9mA   -201.5mA
4.254V    -102.5mA   -101.6mA   -161.8mA
4.264V    -102.9mA   -101.8mA   -29.28mA
4.323V    -106.1mA   -103mA     -112.8mA
5.125V    -125.5mA   -54.58mA   -195mA
5.174V    -127.5mA   -53.44mA   -115.7mA
6.6V      -50.44mA   -44.59mA   -89.59mA
[POWER Clamp]
|   Voltage   I(typ)   I(min)   I(max)
-3.3V     330.7mA    180mA      566.4mA
-2.736V   200mA      135.8mA    401.6mA
-1.647V   138.3mA    65.17mA    197.7mA
-1.459V   117.6mA    55.06mA    168.7mA
-1.082V   66.76mA    35.64mA    126mA
-815.1mV  42.67mA    23.06mA    106.5mA
-3.3mV    2.23mA     1.644mA    59.85mA
46.2mV    1.16mA     1.045mA    48.48mA
313.5mV   86.41uA    94.45uA    19.62mA
491.7mV   74.41uA    72.76uA    3.272mA
570.9mV   69.96uA    68.47uA    464.4uA
6.6V      0A         0A         0A
[Ramp]
R_load = 50
|   typ   min   max
dV/dt_r   0.510106/4.67825e-11   0.4875/7.30155e-11   0.514361/3.50377e-11
dV/dt_f   0.506802/6.7085e-11   0.488924/8.2036e-11   0.514361/6.00805e-11
[Falling Waveform]
V_fixture = 1V
V_fixture_min = 0.95V
V_fixture_max = 1.05V
R_fixture = 50Ohm
C_fixture = 0F
|   Time   V(typ)   V(min)   V(max)
0s        1.575V     1.496V     1.622V
179.4ps   1.596V     1.5V       1.654V
200ps     1.511V     1.462V     1.489V
216.3ps   1.32V      1.385V     1.274V
237.5ps   1.111V     1.199V     1.114V
265.1ps   954.9mV    991.1mV    918mV
291.9ps   838.1mV    884.4mV    776.9mV
325.5ps   732.2mV    790.8mV    694.1mV
408.4ps   681.3mV    672mV      765.9mV
589.2ps   730.2mV    681.4mV    764.4mV
[Rising Waveform]
V_fixture = 1V
V_fixture_min = 0.95V
V_fixture_max = 1.05V
R_fixture = 50Ohm
C_fixture = 0F
|   Time   V(typ)   V(min)   V(max)
0s        724.7mV    686.9mV    764.4mV
165ps     741.7mV    724.2mV    767.2mV
201.7ps   893.8mV    823.9mV    986mV
210.2ps   943.2mV    850.9mV    1.111V
224.3ps   1.098V     908.2mV    1.385V
233ps     1.219V     959.8mV    1.505V
256.2ps   1.469V     1.144V     1.635V
290.7ps   1.589V     1.377V     1.629V
332.5ps   1.585V     1.483V     1.616V
589.2ps   1.575V     1.499V     1.622V
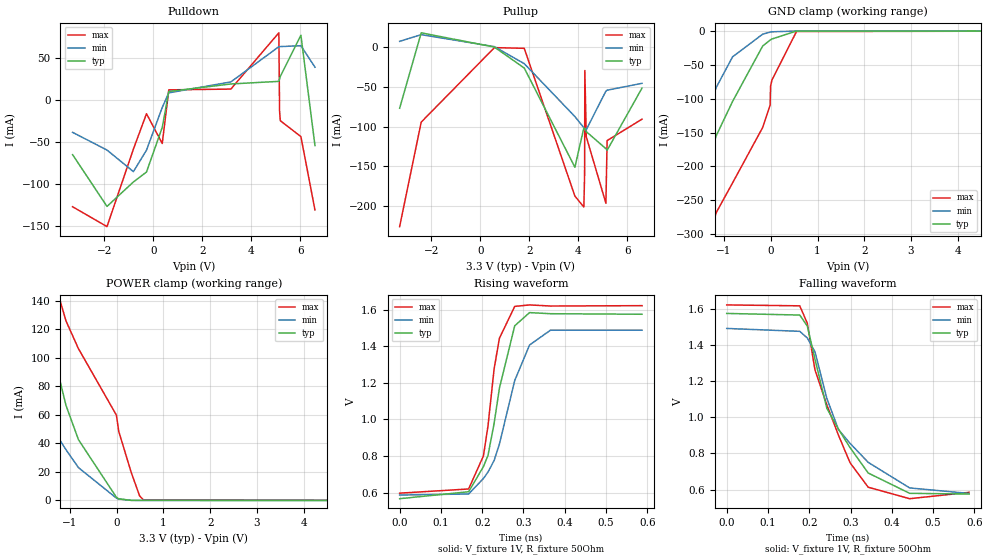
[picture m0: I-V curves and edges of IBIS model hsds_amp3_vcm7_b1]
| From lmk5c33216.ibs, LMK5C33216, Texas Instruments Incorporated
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[Model]   hsds_amp3_vcm7_b1
Model_type   Output
Polarity   Non-Inverting
Vmeas = 1.1
Vref = 1
Cref = 0pF
Rref = 50
|   typ   min   max
C_comp   0.65pF   0.575pF   0.725pF
[Voltage Range]   3.3   3.135   3.465
[Temperature Range]   50   135   -40
[Pullup Reference]   3.3   3.135   3.465
[Pulldown Reference]   0   0   -0
[Power Clamp Reference]   3.3   3.135   3.465
[GND Clamp Reference]   0   0   0
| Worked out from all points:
|   slope of the pulldown table from 0 to 0.495 V, typ, clamps not added: 7.91 ohm
|   slope of the pullup table from 0 to 0.495 V, typ, clamps not added: 48.9 ohm
|   falling waveform, V_fixture 1V, R_fixture 50Ohm: 20-80 % time 105ps typ, 118ps min, 87ps max; typ from 1.57 V to 0.575 V
|   rising waveform, V_fixture 1V, R_fixture 50Ohm: 20-80 % time 50.1ps typ, 65.2ps min, 36ps max; typ from 0.567 V to 1.57 V
[Pulldown]
|   Voltage   I(typ)   I(min)   I(max)
-3.3V     -65.36mA   -38.82mA   -127.3mA
-1.894V   -126.9mA   -59.88mA   -150.9mA
-815.1mV  -97.84mA   -85.53mA   -58.75mA
-280.5mV  -85.97mA   -60.01mA   -16.71mA
363mV     -32.95mA   -9.234mA   -52.1mA
630.3mV   9.777mA    8.134mA    11.68mA
3.165V    18.71mA    21.13mA    12.62mA
5.125V    21.79mA    63mA       79.52mA
5.155V    24.49mA    63.08mA    -13.53mA
5.184V    27.52mA    63.16mA    -24.95mA
6.026V    76.69mA    64.17mA    -43.88mA
6.6V      -54.52mA   38.68mA    -131.1mA
[GND Clamp]
|   Voltage   I(typ)   I(min)   I(max)
-3.3V     -892.9mA   -765.6mA   -1.068A
-1.924V   -314.6mA   -288.5mA   -459.9mA
-1.815V   -287mA     -251.4mA   -425.6mA
-1.478V   -218.2mA   -143.5mA   -333.1mA
-1.162V   -154.3mA   -82.94mA   -268mA
-815.1mV  -104mA     -38.12mA   -224.4mA
-171.6mV  -22.09mA   -4.573mA   -142.5mA
-13.2mV   -13.46mA   -1.685mA   -109.6mA
-3.3mV    -13.01mA   -1.546mA   -81.32mA
26.4mV    -11.77mA   -1.169mA   -72.35mA
551.1mV   0A         -83.65nA   -742.8uA
6.6V      0A         0A         0A
[Pullup]
|   Voltage   I(typ)   I(min)   I(max)
-3.3V     -76.84mA   7.577mA    -226.2mA
-2.419V   18.33mA    16.02mA    -94.35mA
570.9mV   315.5uA    889.3uA    -381.6uA
1.789V    -26.09mA   -20.56mA   -1.217mA
3.858V    -151.3mA   -87.36mA   -187.7mA
4.224V    -101.7mA   -101.5mA   -201.5mA
4.254V    -102.7mA   -102.3mA   -161.7mA
4.264V    -103.1mA   -102.5mA   -29.27mA
4.323V    -106.4mA   -103.9mA   -112.8mA
5.125V    -127.9mA   -55.2mA    -196.8mA
5.174V    -129.9mA   -54.06mA   -117.7mA
6.6V      -51.36mA   -45.42mA   -90.59mA
[POWER Clamp]
|   Voltage   I(typ)   I(min)   I(max)
-3.3V     330.7mA    180mA      566.4mA
-2.736V   200mA      135.8mA    401.6mA
-1.647V   138.3mA    65.17mA    197.7mA
-1.459V   117.6mA    55.06mA    168.7mA
-1.082V   66.76mA    35.64mA    126mA
-815.1mV  42.67mA    23.06mA    106.5mA
-3.3mV    2.23mA     1.644mA    59.85mA
46.2mV    1.16mA     1.045mA    48.48mA
313.5mV   86.42uA    94.45uA    19.62mA
491.7mV   74.41uA    72.76uA    3.272mA
570.9mV   69.96uA    68.47uA    464.3uA
6.6V      0A         0A         0A
[Ramp]
R_load = 50
|   typ   min   max
dV/dt_r   0.604516/4.99892e-11   0.540097/6.49917e-11   0.614666/3.58825e-11
dV/dt_f   0.59889/1.04684e-10   0.547153/1.16838e-10   0.621234/8.65945e-11
[Falling Waveform]
V_fixture = 1V
V_fixture_min = 0.95V
V_fixture_max = 1.05V
R_fixture = 50Ohm
C_fixture = 0F
|   Time   V(typ)   V(min)   V(max)
0s        1.573V     1.49V      1.62V
177ps     1.564V     1.474V     1.615V
195.3ps   1.503V     1.437V     1.518V
213.8ps   1.32V      1.361V     1.261V
242.5ps   1.049V     1.104V     1.068V
270.7ps   933.9mV    931.2mV    900.2mV
298.7ps   831.9mV    855.3mV    748.3mV
342.7ps   691.1mV    750.1mV    612.6mV
443.2ps   578.9mV    608.7mV    549.2mV
587.2ps   574.8mV    578.2mV    584.2mV
[Rising Waveform]
V_fixture = 1V
V_fixture_min = 0.95V
V_fixture_max = 1.05V
R_fixture = 50Ohm
C_fixture = 0F
|   Time   V(typ)   V(min)   V(max)
0s        566.5mV    586.5mV    596.8mV
167.1ps   604.4mV    592.2mV    619.5mV
203ps     741.8mV    677mV      800.2mV
214ps     802.6mV    711.7mV    963.8mV
228.9ps   978.2mV    775.3mV    1.276V
241.7ps   1.17V      864.7mV    1.443V
278.8ps   1.511V     1.212V     1.617V
314.7ps   1.583V     1.406V     1.625V
365.4ps   1.577V     1.487V     1.619V
587.2ps   1.574V     1.487V     1.621V
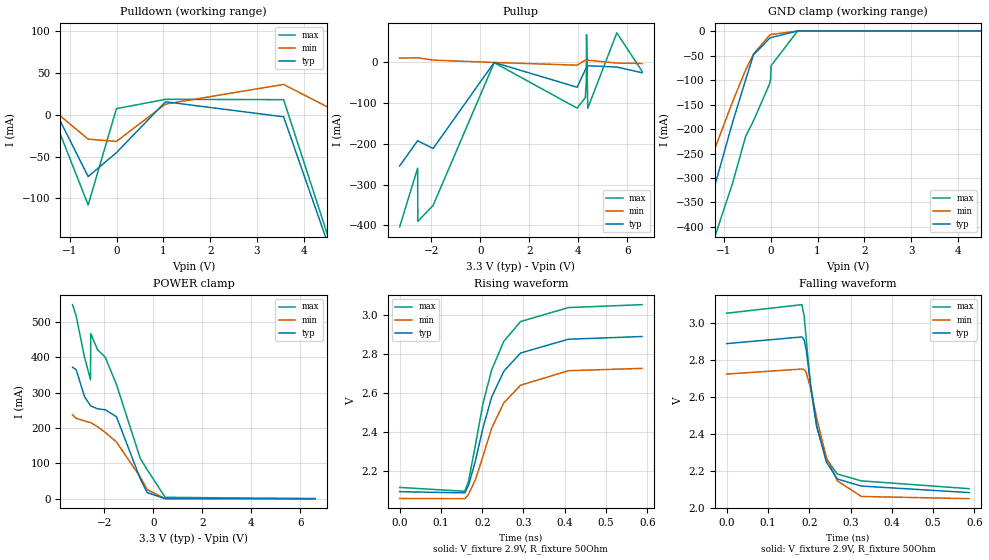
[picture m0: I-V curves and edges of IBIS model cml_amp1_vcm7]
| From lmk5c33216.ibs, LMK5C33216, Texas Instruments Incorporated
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[Model]   cml_amp1_vcm7
Model_type   Output
Polarity   Non-Inverting
Vmeas = 2.5
Vref = 2.9
Cref = 0pF
Rref = 50
|   typ   min   max
C_comp   0.65pF   0.575pF   0.725pF
[Voltage Range]   3.3   3.135   3.465
[Temperature Range]   50   135   -40
[Pullup Reference]   3.3   3.135   3.465
[Pulldown Reference]   0   -0   -0
[Power Clamp Reference]   3.3   3.135   3.465
[GND Clamp Reference]   0   0   0
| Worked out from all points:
|   slope of the pulldown table from 0 to 0.495 V, typ, clamps not added: 16.6 ohm
|   falling waveform, V_fixture 2.9V, R_fixture 50Ohm: 20-80 % time 42.3ps typ, 48.8ps min, 41.6ps max; typ from 2.89 V to 2.08 V
|   rising waveform, V_fixture 2.9V, R_fixture 50Ohm: 20-80 % time 74.4ps typ, 78.7ps min, 71.4ps max; typ from 2.09 V to 2.89 V
[Pulldown]
|   Voltage   I(typ)   I(min)   I(max)
-3.3V     -23.88mA   4.794mA    59.35mA
-2.567V   -17.81mA   4.377mA    104.4mA
-2.558V   -17.26mA   4.312mA    33.76mA
-1.538V   29.93mA    14.52mA    24.42mA
-607.2mV  -73.75mA   -28.97mA   -107.7mA
-3.3mV    -45.12mA   -31.65mA   7.584mA
1.046V    15.79mA    13.07mA    18.75mA
3.571V    -2.224mA   36.55mA    18.35mA
4.729V    -188.2mA   3.284mA    -181.5mA
5.333V    -196.2mA   9.137mA    -328.2mA
6.125V    -171.3mA   8.553mA    -373.4mA
6.6V      -281.1mA   12.69mA    -448.7mA
[GND Clamp]
|   Voltage   I(typ)   I(min)   I(max)
-3.3V     -1.161A    -986.5mA   -1.48A
-1.785V   -501.2mA   -417.8mA   -665mA
-1.508V   -420.3mA   -321mA     -551.3mA
-1.211V   -320.6mA   -244.1mA   -424.5mA
-815.1mV  -186.1mA   -144.2mA   -310.3mA
-537.9mV  -99.97mA   -79.46mA   -215.4mA
-369.6mV  -48.73mA   -47.08mA   -183.3mA
-23.1mV   -14.69mA   -8.348mA   -107.4mA
-3.3mV    -13.79mA   -7.453mA   -98.57mA
6.6mV     -13.36mA   -7.036mA   -70.77mA
570.9mV   0A         -9.437uA   -391.3uA
6.6V      0A         0A         0A
[Pullup]
|   Voltage   I(typ)   I(min)   I(max)
-3.3V     -254.1mA   10.89mA    -403.7mA
-2.567V   -192.3mA   11.52mA    -259.6mA
-2.558V   -192.6mA   11.5mA     -390.2mA
-1.934V   -211.3mA   5.751mA    -351mA
561mV     -845.6nA   5.388uA    -544.2uA
3.947V    -60.89mA   -6.674mA   -112.1mA
4.283V    -17.76mA   5.893mA    -86.42mA
4.323V    -13.49mA   5.806mA    -47.18mA
4.333V    -12.48mA   5.767mA    68.06mA
4.382V    -8.14mA    5.672mA    -112.5mA
5.57V     -11.22mA   -1.522mA   72.76mA
6.6V      -25.24mA   -2.567mA   -21.52mA
[POWER Clamp]
|   Voltage   I(typ)   I(min)   I(max)
-3.3V     371.7mA    237.1mA    548.6mA
-3.151V   364.4mA    227.2mA    516.2mA
-2.815V   288.8mA    219.8mA    400.7mA
-2.567V   262.8mA    215.2mA    336.7mA
-2.558V   262.4mA    214.9mA    466.8mA
-2.28V    254.1mA    203.6mA    421.2mA
-1.964V   251.4mA    187.3mA    399.9mA
-1.508V   231.7mA    160.3mA    322.9mA
-537.9mV  56.76mA    61.47mA    114.3mA
-250.8mV  17.02mA    25.27mA    81.75mA
481.8mV   75.9uA     118.2uA    3.912mA
6.6V      0A         0A         0A
[Ramp]
R_load = 50
|   typ   min   max
dV/dt_r   0.479642/7.41193e-11   0.402148/7.81694e-11   0.564463/7.15152e-11
dV/dt_f   0.482068/4.2228e-11   0.402938/4.87327e-11   0.567225/4.13018e-11
[Falling Waveform]
V_fixture = 2.9V
V_fixture_min = 2.735V
V_fixture_max = 3.065V
R_fixture = 50Ohm
C_fixture = 0F
|   Time   V(typ)   V(min)   V(max)
0s        2.888V     2.724V     3.052V
182ps     2.924V     2.751V     3.098V
187.4ps   2.908V     2.748V     3.039V
192.4ps   2.857V     2.733V     2.917V
203.7ps   2.662V     2.645V     2.643V
218.1ps   2.443V     2.483V     2.438V
241.3ps   2.25V      2.275V     2.265V
268ps     2.158V     2.148V     2.185V
326.2ps   2.12V      2.064V     2.148V
587.3ps   2.085V     2.052V     2.106V
[Rising Waveform]
V_fixture = 2.9V
V_fixture_min = 2.735V
V_fixture_max = 3.065V
R_fixture = 50Ohm
C_fixture = 0F
|   Time   V(typ)   V(min)   V(max)
0s        2.092V     2.057V     2.114V
158ps     2.086V     2.056V     2.094V
166.8ps   2.124V     2.078V     2.145V
183.3ps   2.249V     2.153V     2.329V
201.8ps   2.42V      2.273V     2.546V
223ps     2.58V      2.42V      2.72V
252.3ps   2.712V     2.549V     2.866V
292.9ps   2.806V     2.64V      2.968V
408.8ps   2.877V     2.715V     3.04V
587.3ps   2.891V     2.727V     3.055V
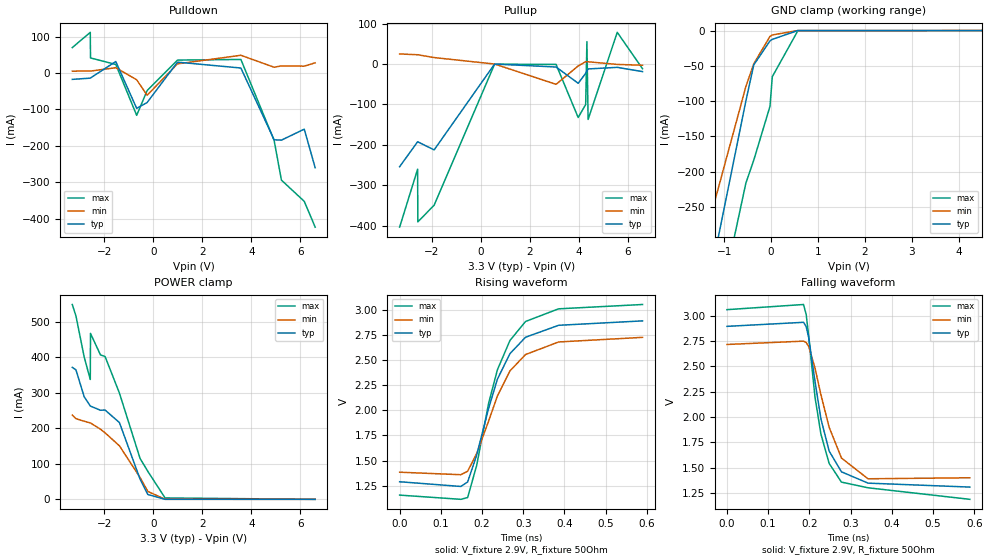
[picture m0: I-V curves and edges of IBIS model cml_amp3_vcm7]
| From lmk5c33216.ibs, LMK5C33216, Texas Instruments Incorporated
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[Model]   cml_amp3_vcm7
Model_type   Output
Polarity   Non-Inverting
Vmeas = 2.05
Vref = 2.9
Cref = 0pF
Rref = 50
|   typ   min   max
C_comp   0.65pF   0.575pF   0.725pF
[Voltage Range]   3.3   3.135   3.465
[Temperature Range]   50   135   -40
[Pullup Reference]   3.3   3.135   3.465
[Pulldown Reference]   -0   -0   -0
[Power Clamp Reference]   3.3   3.135   3.465
[GND Clamp Reference]   0   0   0
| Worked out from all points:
|   slope of the pulldown table from 0 to 0.495 V, typ, clamps not added: 12.6 ohm
|   falling waveform, V_fixture 2.9V, R_fixture 50Ohm: 20-80 % time 45.9ps typ, 53.5ps min, 45.2ps max; typ from 2.9 V to 1.31 V
|   rising waveform, V_fixture 2.9V, R_fixture 50Ohm: 20-80 % time 77.8ps typ, 85ps min, 73.7ps max; typ from 1.29 V to 2.89 V
[Pulldown]
|   Voltage   I(typ)   I(min)   I(max)
-3.3V     -17.42mA   5.232mA    69.94mA
-2.567V   -14mA      5.467mA    111.9mA
-2.558V   -13.48mA   5.351mA    41.51mA
-1.528V   31.69mA    14.68mA    23.6mA
-676.5mV  -97.01mA   -18.45mA   -116.2mA
-250.8mV  -81.06mA   -61.11mA   -48.32mA
986.7mV   29.92mA    25.16mA    35.64mA
3.571V    13.81mA    48.82mA    37.33mA
4.927V    -183.4mA   15.94mA    -185.4mA
5.224V    -184.4mA   19.61mA    -294.3mA
6.154V    -154.2mA   18.95mA    -352.5mA
6.6V      -260.3mA   28.06mA    -423.5mA
[GND Clamp]
|   Voltage   I(typ)   I(min)   I(max)
-3.3V     -1.161A    -986.5mA   -1.48A
-1.983V   -563.2mA   -494.7mA   -750mA
-1.884V   -529.4mA   -456.3mA   -707.9mA
-1.607V   -450.1mA   -352.4mA   -589mA
-1.409V   -387.6mA   -293.5mA   -509.1mA
-1.211V   -320.6mA   -244.1mA   -424.8mA
-537.9mV  -99.97mA   -79.46mA   -216.2mA
-369.6mV  -48.73mA   -47.08mA   -183.7mA
-23.1mV   -14.69mA   -8.348mA   -107.4mA
26.4mV    -12.51mA   -6.259mA   -65.41mA
570.9mV   0A         -9.437uA   -392uA
6.6V      0A         0A         0A
[Pullup]
|   Voltage   I(typ)   I(min)   I(max)
-3.3V     -254.1mA   25.01mA    -403.7mA
-2.567V   -192.3mA   23.03mA    -260.2mA
-2.558V   -192.6mA   23.05mA    -390.6mA
-1.894V   -212.5mA   16.05mA    -349.4mA
570.9mV   3.115uA    18.71uA    -392.2uA
3.076V    -7.324mA   -50.19mA   -913.6uA
3.977V    -47.56mA   -4.709mA   -132.3mA
4.283V    -23.08mA   5.888mA    -100.2mA
4.333V    -17.07mA   5.754mA    55.51mA
4.382V    -12.11mA   5.623mA    -137.1mA
5.57V     -8.153mA   -948.9uA   78.53mA
6.6V      -18.7mA    -2.893mA   -11.58mA
[POWER Clamp]
|   Voltage   I(typ)   I(min)   I(max)
-3.3V     371.7mA    237.1mA    548.6mA
-3.151V   364.4mA    227.2mA    516.2mA
-2.815V   288.8mA    219.8mA    400.7mA
-2.567V   262.8mA    215.2mA    337.4mA
-2.558V   262.4mA    214.9mA    467.2mA
-2.152V   250.9mA    197.5mA    406.7mA
-1.964V   251.4mA    187.3mA    402.2mA
-1.379V   216.1mA    150.7mA    299.1mA
-537.9mV  56.76mA    61.47mA    115.1mA
-221.1mV  13.55mA    22.33mA    78.75mA
481.8mV   75.9uA     118.2uA    3.912mA
6.6V      0A         0A         0A
[Ramp]
R_load = 50
|   typ   min   max
dV/dt_r   0.960397/7.72004e-11   0.804939/8.44995e-11   1.13854/7.33299e-11
dV/dt_f   0.95264/4.59287e-11   0.789917/5.34448e-11   1.12409/4.50437e-11
[Falling Waveform]
V_fixture = 2.9V
V_fixture_min = 2.735V
V_fixture_max = 3.065V
R_fixture = 50Ohm
C_fixture = 0F
|   Time   V(typ)   V(min)   V(max)
0s        2.896V     2.717V     3.061V
185.8ps   2.936V     2.75V      3.112V
192.3ps   2.893V     2.736V     3.012V
198.3ps   2.785V     2.697V     2.798V
213.7ps   2.35V      2.483V     2.195V
228ps     1.982V     2.22V      1.831V
247.9ps   1.664V     1.899V     1.542V
277.8ps   1.459V     1.595V     1.357V
342.3ps   1.347V     1.39V      1.301V
589.4ps   1.308V     1.4V       1.187V
[Rising Waveform]
V_fixture = 2.9V
V_fixture_min = 2.735V
V_fixture_max = 3.065V
R_fixture = 50Ohm
C_fixture = 0F
|   Time   V(typ)   V(min)   V(max)
0s        1.289V     1.384V     1.156V
148.6ps   1.242V     1.359V     1.114V
165.1ps   1.287V     1.394V     1.132V
186.9ps   1.554V     1.569V     1.451V
216ps     2.021V     1.894V     2.071V
237.3ps   2.31V      2.143V     2.404V
267.7ps   2.564V     2.392V     2.695V
305.5ps   2.727V     2.555V     2.884V
385.7ps   2.846V     2.68V      3.01V
589.4ps   2.89V      2.726V     3.053V
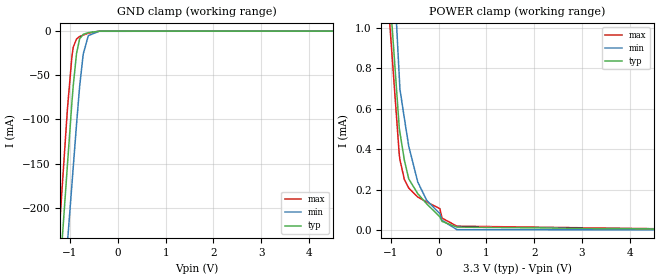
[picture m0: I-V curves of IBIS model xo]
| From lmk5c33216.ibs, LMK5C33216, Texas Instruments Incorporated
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|   xo Model
[Model]   xo
Model_type   Input
Vinl = 0.8
Vinh = 1.4
|   typ   min   max
C_comp   7.8306E-13  7.5396E-13  8.1779E-13
| Where nom  PVT is Nominal Process, 3.3V,   27C
|   Fast PVT is Strong Process,  3.45V, -40C
|   Slow PVT is Weak Process,   3.15V, 125C
[Voltage Range]   3.3   3.15   3.45
|Junction Temperature
[Temperature Range]   27   125   -40
[Power Clamp Reference]   3.3   3.15   3.45
[GND Clamp Reference]   0   0   0
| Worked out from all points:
|   GND clamp passes 1 mA (typ) near -0.52 V on its own axis
[GND Clamp]
|   Voltage   I(typ)   I(min)   I(max)
-3.3V     -1.89A     -1.85A     -1.924A
-1.554V   -536.5mA   -595.7mA   -494.4mA
-1.209V   -271mA     -350.3mA   -213.3mA
-1.055V   -152.3mA   -240.5mA   -88.79mA
-959.5mV  -80.12mA   -173.1mA   -28.39mA
-931.9mV  -61.47mA   -153.6mA   -18.1mA
-863.3mV  -25.29mA   -105.2mA   -8.916mA
-798.5mV  -8.723mA   -62.73mA   -6.084mA
-722.8mV  -3.705mA   -25.97mA   -4.548mA
-616.4mV  -1.772mA   -5.044mA   -2.389mA
-391.5mV  -125.1uA   -230uA     -85.78uA
6.6V      0A         0A         0A
[POWER Clamp]
|   Voltage   I(typ)   I(min)   I(max)
-3.3V     596.7mA    583.7mA    615.5mA
-1.149V   1.595mA    2.243mA    1.429mA
-824.2mV  503.4uA    757.5uA    372uA
-811.3mV  483.8uA    698.2uA    348.6uA
-717.7mV  345.2uA    552.4uA    249.8uA
-625.8mV  252.6uA    414.1uA    207.4uA
-436.5mV  179.4uA    236.4uA    162.8uA
-247.3mV  128.5uA    145.7uA    138.3uA
25.25mV   64.84uA    80.51uA    105.6uA
69mV      42.45uA    48.52uA    58.92uA
380.6mV   14.2uA     1.59uA     18.83uA
6.6V      0A         0A         0A
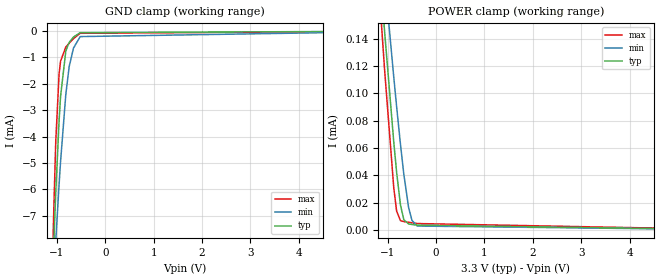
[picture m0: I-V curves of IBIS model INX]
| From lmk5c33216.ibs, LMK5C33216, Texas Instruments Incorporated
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|   INX Model
[Model]   INX
Model_type   Input
Vinl = 0.8
Vinh = 1.4
|   typ   min   max
C_comp   1.68904E-12   1.65061E-12   1.68905E-12
| Where nom  PVT is Nominal Process, 3.3V,   27C
|   Fast PVT is Strong Process,  3.45V, -40C
|   Slow PVT is Weak Process,   3.15V, 125C
[Voltage Range]   3.3   3.15   3.45
|Junction Temperature
[Temperature Range]   27   125   -40
[Power Clamp Reference]   3.3   3.15   3.45
[GND Clamp Reference]   0   0   0
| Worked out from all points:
|   GND clamp passes 1 mA (typ) near -0.83 V on its own axis
[GND Clamp]
|   Voltage   I(typ)   I(min)   I(max)
-3.3V     -162.6mA   -102.4mA   -292.3mA
-1.092V   -9.551mA   -10.27mA   -9.051mA
-1.073V   -8.522mA   -9.591mA   -7.461mA
-1.063V   -8.021mA   -9.255mA   -6.72mA
-1.023V   -6.131mA   -7.943mA   -4.18mA
-953.7mV  -3.379mA   -5.798mA   -1.608mA
-924mV    -2.48mA    -4.953mA   -1.141mA
-815.1mV  -755.5uA   -2.398mA   -604.3uA
-745.8mV  -427.3uA   -1.348mA   -457.8uA
-656.7mV  -225.2uA   -645.4uA   -287uA
-518.1mV  -59.62uA   -208.3uA   -83.82uA
6.6V      0A         0A         0A
[POWER Clamp]
|   Voltage   I(typ)   I(min)   I(max)
-3.3V     1.223mA    1.119mA    1.349mA
-1.251V   230.8uA    259.1uA    214.6uA
-1.132V   176.1uA    211.5uA    152.2uA
-1.063V   144.8uA    184.1uA    116.8uA
-874.5mV  64.42uA    111.9uA    30.87uA
-815.1mV  42.1uA     90.16uA    13.8uA
-735.9mV  18.32uA    62.67uA    6.81uA
-666.6mV  7.522uA    40.81uA    6.118uA
-567.6mV  4.429uA    16.41uA    5.603uA
-498.3mV  4.012uA    7.045uA    5.252uA
-389.4mV  3.491uA    2.875uA    4.702uA
6.6V      0A         0A         0A
